VERSION 5.4 ;
NAMESCASESENSITIVE ON ;
BUSBITCHARS "[]" ;
DIVIDERCHAR "/" ;
UNITS
  DATABASE MICRONS 2000 ;
END UNITS
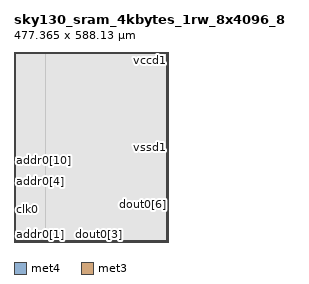
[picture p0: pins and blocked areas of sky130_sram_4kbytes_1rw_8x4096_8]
MACRO sky130_sram_4kbytes_1rw_8x4096_8
   CLASS BLOCK ;
   SIZE 477.365 BY 588.13 ;
   SYMMETRY X Y R90 ;
   PIN din0[0]
      DIRECTION INPUT ;
      PORT
         LAYER met4 ;
         RECT  96.96 0.0 97.34 0.38 ;
      END
   END din0[0]
   PIN din0[1]
      DIRECTION INPUT ;
      PORT
         LAYER met4 ;
         RECT  102.8 0.0 103.18 0.38 ;
      END
   END din0[1]
   PIN din0[2]
      DIRECTION INPUT ;
      PORT
         LAYER met4 ;
         RECT  108.64 0.0 109.02 0.38 ;
      END
   END din0[2]
   PIN din0[3]
      DIRECTION INPUT ;
      PORT
         LAYER met4 ;
         RECT  114.48 0.0 114.86 0.38 ;
      END
   END din0[3]
   PIN din0[4]
      DIRECTION INPUT ;
      PORT
         LAYER met4 ;
         RECT  120.32 0.0 120.7 0.38 ;
      END
   END din0[4]
   PIN din0[5]
      DIRECTION INPUT ;
      PORT
         LAYER met4 ;
         RECT  126.16 0.0 126.54 0.38 ;
      END
   END din0[5]
   PIN din0[6]
      DIRECTION INPUT ;
      PORT
         LAYER met4 ;
         RECT  132.0 0.0 132.38 0.38 ;
      END
   END din0[6]
   PIN din0[7]
      DIRECTION INPUT ;
      PORT
         LAYER met4 ;
         RECT  137.84 0.0 138.22 0.38 ;
      END
   END din0[7]
   PIN din0[8]
      DIRECTION INPUT ;
      PORT
         LAYER met4 ;
         RECT  143.68 0.0 144.06 0.38 ;
      END
   END din0[8]
   PIN addr0[0]
      DIRECTION INPUT ;
      PORT
         LAYER met4 ;
         RECT  73.6 0.0 73.98 0.38 ;
      END
   END addr0[0]
   PIN addr0[1]
      DIRECTION INPUT ;
      PORT
         LAYER met4 ;
         RECT  79.44 0.0 79.82 0.38 ;
      END
   END addr0[1]
   PIN addr0[2]
      DIRECTION INPUT ;
      PORT
         LAYER met4 ;
         RECT  85.28 0.0 85.66 0.38 ;
      END
   END addr0[2]
   PIN addr0[3]
      DIRECTION INPUT ;
      PORT
         LAYER met4 ;
         RECT  91.12 0.0 91.5 0.38 ;
      END
   END addr0[3]
   PIN addr0[4]
      DIRECTION INPUT ;
      PORT
         LAYER met3 ;
         RECT  0.0 210.21 0.38 210.59 ;
      END
   END addr0[4]
   PIN addr0[5]
      DIRECTION INPUT ;
      PORT
         LAYER met3 ;
         RECT  0.0 218.71 0.38 219.09 ;
      END
   END addr0[5]
   PIN addr0[6]
      DIRECTION INPUT ;
      PORT
         LAYER met3 ;
         RECT  0.0 224.35 0.38 224.73 ;
      END
   END addr0[6]
   PIN addr0[7]
      DIRECTION INPUT ;
      PORT
         LAYER met3 ;
         RECT  0.0 232.85 0.38 233.23 ;
      END
   END addr0[7]
   PIN addr0[8]
      DIRECTION INPUT ;
      PORT
         LAYER met3 ;
         RECT  0.0 238.49 0.38 238.87 ;
      END
   END addr0[8]
   PIN addr0[9]
      DIRECTION INPUT ;
      PORT
         LAYER met3 ;
         RECT  0.0 246.99 0.38 247.37 ;
      END
   END addr0[9]
   PIN addr0[10]
      DIRECTION INPUT ;
      PORT
         LAYER met3 ;
         RECT  0.0 252.385 0.38 252.765 ;
      END
   END addr0[10]
   PIN addr0[11]
      DIRECTION INPUT ;
      PORT
         LAYER met3 ;
         RECT  0.0 260.785 0.38 261.165 ;
      END
   END addr0[11]
   PIN addr0[12]
      DIRECTION INPUT ;
      PORT
         LAYER met3 ;
         RECT  0.0 266.77 0.38 267.15 ;
      END
   END addr0[12]
   PIN csb0
      DIRECTION INPUT ;
      PORT
         LAYER met3 ;
         RECT  0.0 100.55 0.38 100.93 ;
      END
   END csb0
   PIN web0
      DIRECTION INPUT ;
      PORT
         LAYER met3 ;
         RECT  0.0 109.05 0.38 109.43 ;
      END
   END web0
   PIN clk0
      DIRECTION INPUT ;
      PORT
         LAYER met3 ;
         RECT  0.0 101.24 0.38 101.62 ;
      END
   END clk0
   PIN spare_wen0
      DIRECTION INPUT ;
      PORT
         LAYER met4 ;
         RECT  149.52 0.0 149.9 0.38 ;
      END
   END spare_wen0
   PIN dout0[0]
      DIRECTION OUTPUT ;
      PORT
         LAYER met4 ;
         RECT  141.875 0.0 142.255 0.38 ;
      END
   END dout0[0]
   PIN dout0[1]
      DIRECTION OUTPUT ;
      PORT
         LAYER met4 ;
         RECT  182.59 0.0 182.97 0.38 ;
      END
   END dout0[1]
   PIN dout0[2]
      DIRECTION OUTPUT ;
      PORT
         LAYER met4 ;
         RECT  222.59 0.0 222.97 0.38 ;
      END
   END dout0[2]
   PIN dout0[3]
      DIRECTION OUTPUT ;
      PORT
         LAYER met4 ;
         RECT  262.59 0.0 262.97 0.38 ;
      END
   END dout0[3]
   PIN dout0[4]
      DIRECTION OUTPUT ;
      PORT
         LAYER met4 ;
         RECT  302.59 0.0 302.97 0.38 ;
      END
   END dout0[4]
   PIN dout0[5]
      DIRECTION OUTPUT ;
      PORT
         LAYER met4 ;
         RECT  342.59 0.0 342.97 0.38 ;
      END
   END dout0[5]
   PIN dout0[6]
      DIRECTION OUTPUT ;
      PORT
         LAYER met3 ;
         RECT  476.985 116.01 477.365 116.39 ;
      END
   END dout0[6]
   PIN dout0[7]
      DIRECTION OUTPUT ;
      PORT
         LAYER met3 ;
         RECT  476.985 117.5 477.365 117.88 ;
      END
   END dout0[7]
   PIN dout0[8]
      DIRECTION OUTPUT ;
      PORT
         LAYER met3 ;
         RECT  476.985 116.755 477.365 117.135 ;
      END
   END dout0[8]
   PIN vccd1
      DIRECTION INOUT ;
      USE POWER ; 
      SHAPE ABUTMENT ; 
      PORT
         LAYER met3 ;
         RECT  0.0 586.39 477.365 588.13 ;
         LAYER met3 ;
         RECT  0.0 0.0 477.365 1.74 ;
         LAYER met4 ;
         RECT  0.0 0.0 1.74 588.13 ;
         LAYER met4 ;
         RECT  475.625 0.0 477.365 588.13 ;
      END
   END vccd1
   PIN vssd1
      DIRECTION INOUT ;
      USE GROUND ; 
      SHAPE ABUTMENT ; 
      PORT
         LAYER met4 ;
         RECT  472.145 3.48 473.885 584.65 ;
         LAYER met4 ;
         RECT  3.48 3.48 5.22 584.65 ;
         LAYER met3 ;
         RECT  3.48 3.48 473.885 5.22 ;
         LAYER met3 ;
         RECT  3.48 582.91 473.885 584.65 ;
      END
   END vssd1
   OBS
   LAYER  met1 ;
      RECT  0.62 0.62 476.745 587.51 ;
   LAYER  met2 ;
      RECT  0.62 0.62 476.745 587.51 ;
   LAYER  met3 ;
      RECT  0.98 209.61 476.745 211.19 ;
      RECT  0.62 211.19 0.98 218.11 ;
      RECT  0.62 219.69 0.98 223.75 ;
      RECT  0.62 225.33 0.98 232.25 ;
      RECT  0.62 233.83 0.98 237.89 ;
      RECT  0.62 239.47 0.98 246.39 ;
      RECT  0.62 247.97 0.98 251.785 ;
      RECT  0.62 253.365 0.98 260.185 ;
      RECT  0.62 261.765 0.98 266.17 ;
      RECT  0.62 110.03 0.98 209.61 ;
      RECT  0.62 102.22 0.98 108.45 ;
      RECT  0.98 115.41 476.385 116.99 ;
      RECT  0.98 116.99 476.385 209.61 ;
      RECT  476.385 118.48 476.745 209.61 ;
      RECT  0.62 267.75 0.98 585.79 ;
      RECT  0.62 2.34 0.98 99.95 ;
      RECT  476.385 2.34 476.745 115.41 ;
      RECT  0.98 2.34 2.88 2.88 ;
      RECT  0.98 2.88 2.88 5.82 ;
      RECT  0.98 5.82 2.88 115.41 ;
      RECT  2.88 2.34 474.485 2.88 ;
      RECT  2.88 5.82 474.485 115.41 ;
      RECT  474.485 2.34 476.385 2.88 ;
      RECT  474.485 2.88 476.385 5.82 ;
      RECT  474.485 5.82 476.385 115.41 ;
      RECT  0.98 211.19 2.88 582.31 ;
      RECT  0.98 582.31 2.88 585.25 ;
      RECT  0.98 585.25 2.88 585.79 ;
      RECT  2.88 211.19 474.485 582.31 ;
      RECT  2.88 585.25 474.485 585.79 ;
      RECT  474.485 211.19 476.745 582.31 ;
      RECT  474.485 582.31 476.745 585.25 ;
      RECT  474.485 585.25 476.745 585.79 ;
   LAYER  met4 ;
      RECT  96.36 0.98 97.94 587.51 ;
      RECT  97.94 0.62 102.2 0.98 ;
      RECT  103.78 0.62 108.04 0.98 ;
      RECT  109.62 0.62 113.88 0.98 ;
      RECT  115.46 0.62 119.72 0.98 ;
      RECT  121.3 0.62 125.56 0.98 ;
      RECT  127.14 0.62 131.4 0.98 ;
      RECT  132.98 0.62 137.24 0.98 ;
      RECT  74.58 0.62 78.84 0.98 ;
      RECT  80.42 0.62 84.68 0.98 ;
      RECT  86.26 0.62 90.52 0.98 ;
      RECT  92.1 0.62 96.36 0.98 ;
      RECT  144.66 0.62 148.92 0.98 ;
      RECT  138.82 0.62 141.275 0.98 ;
      RECT  142.855 0.62 143.08 0.98 ;
      RECT  150.5 0.62 181.99 0.98 ;
      RECT  183.57 0.62 221.99 0.98 ;
      RECT  223.57 0.62 261.99 0.98 ;
      RECT  263.57 0.62 301.99 0.98 ;
      RECT  303.57 0.62 341.99 0.98 ;
      RECT  2.34 0.62 73.0 0.98 ;
      RECT  343.57 0.62 475.025 0.98 ;
      RECT  97.94 0.98 471.545 2.88 ;
      RECT  97.94 2.88 471.545 585.25 ;
      RECT  97.94 585.25 471.545 587.51 ;
      RECT  471.545 0.98 474.485 2.88 ;
      RECT  471.545 585.25 474.485 587.51 ;
      RECT  474.485 0.98 475.025 2.88 ;
      RECT  474.485 2.88 475.025 585.25 ;
      RECT  474.485 585.25 475.025 587.51 ;
      RECT  2.34 0.98 2.88 2.88 ;
      RECT  2.34 2.88 2.88 585.25 ;
      RECT  2.34 585.25 2.88 587.51 ;
      RECT  2.88 0.98 5.82 2.88 ;
      RECT  2.88 585.25 5.82 587.51 ;
      RECT  5.82 0.98 96.36 2.88 ;
      RECT  5.82 2.88 96.36 585.25 ;
      RECT  5.82 585.25 96.36 587.51 ;
   END
END    sky130_sram_4kbytes_1rw_8x4096_8
END    LIBRARY
